VERSION 5.8 ;
BUSBITCHARS "[]" ;
DIVIDERCHAR "/" ;
UNITS
  DATABASE MICRONS 1000 ;
END UNITS
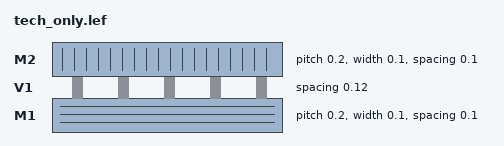
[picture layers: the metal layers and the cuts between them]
LAYER M1
  TYPE ROUTING ;
  DIRECTION HORIZONTAL ;
  PITCH 0.2 ;
  WIDTH 0.1 ;
  SPACING 0.1 ;
END M1
LAYER V1
  TYPE CUT ;
  SPACING 0.12 ;
END V1
LAYER M2
  TYPE ROUTING ;
  DIRECTION VERTICAL ;
  PITCH 0.2 ;
  WIDTH 0.1 ;
  SPACING 0.1 ;
END M2
END LIBRARY
